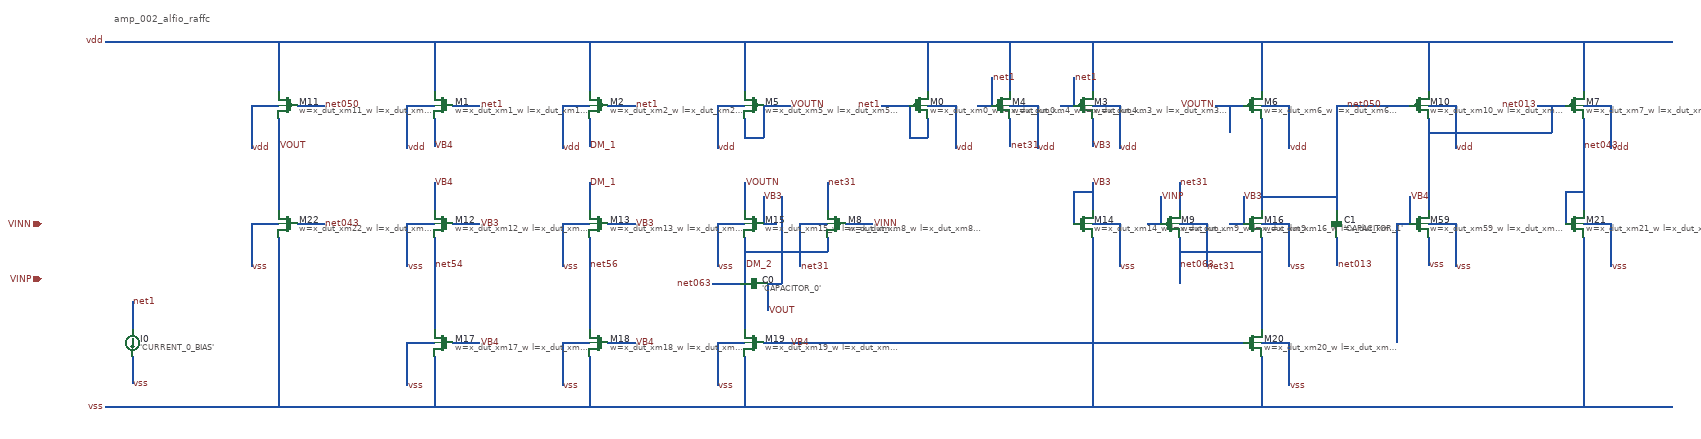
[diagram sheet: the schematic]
v {xschem version=3.4.6 file_version=1.2}
G {}
K {}
V {}
S {}
E {}
T {amp_002_alfio_raffc} -1740 -200 0 0 0.4 0.4 {}
C {devices/capa_np.sym} -340 390 1 0 {name=C0 value='CAPACITOR_0'}
C {devices/capa_np.sym} 935 260 0 0 {name=C1 value='CAPACITOR_1'}
C {devices/isource_np.sym} -1700 520 0 0 {name=I0 value='CURRENT_0_BIAS'}
C {devices/sg13_lv_pmos_np.sym} 20 0 0 0 {name=M0 model=sg13_lv_pmos spiceprefix=X w=x_dut_xm0_w l=x_dut_xm0_l m=x_dut_xm0_m}
C {devices/sg13_lv_pmos_np.sym} -1020 0 0 1 {name=M1 model=sg13_lv_pmos spiceprefix=X w=x_dut_xm1_w l=x_dut_xm1_l m=x_dut_xm1_m}
C {devices/sg13_lv_pmos_np.sym} 1115 0 0 0 {name=M10 model=sg13_lv_pmos spiceprefix=X w=x_dut_xm10_w l=x_dut_xm10_l m=x_dut_xm10_m}
C {devices/sg13_lv_pmos_np.sym} -1360 0 0 1 {name=M11 model=sg13_lv_pmos spiceprefix=X w=x_dut_xm11_w l=x_dut_xm11_l m=x_dut_xm11_m}
C {devices/sg13_lv_nmos_np.sym} -1020 260 0 1 {name=M12 model=sg13_lv_nmos spiceprefix=X w=x_dut_xm12_w l=x_dut_xm12_l m=x_dut_xm12_m}
C {devices/sg13_lv_nmos_np.sym} -680 260 0 1 {name=M13 model=sg13_lv_nmos spiceprefix=X w=x_dut_xm13_w l=x_dut_xm13_l m=x_dut_xm13_m}
C {devices/sg13_lv_nmos_np.sym} 380 260 0 0 {name=M14 model=sg13_lv_nmos spiceprefix=X w=x_dut_xm14_w l=x_dut_xm14_l m=x_dut_xm14_m}
C {devices/sg13_lv_nmos_np.sym} -340 260 0 1 {name=M15 model=sg13_lv_nmos spiceprefix=X w=x_dut_xm15_w l=x_dut_xm15_l m=x_dut_xm15_m}
C {devices/sg13_lv_nmos_np.sym} 750 260 0 0 {name=M16 model=sg13_lv_nmos spiceprefix=X w=x_dut_xm16_w l=x_dut_xm16_l m=x_dut_xm16_m}
C {devices/sg13_lv_nmos_np.sym} -1020 520 0 1 {name=M17 model=sg13_lv_nmos spiceprefix=X w=x_dut_xm17_w l=x_dut_xm17_l m=x_dut_xm17_m}
C {devices/sg13_lv_nmos_np.sym} -680 520 0 1 {name=M18 model=sg13_lv_nmos spiceprefix=X w=x_dut_xm18_w l=x_dut_xm18_l m=x_dut_xm18_m}
C {devices/sg13_lv_nmos_np.sym} -340 520 0 1 {name=M19 model=sg13_lv_nmos spiceprefix=X w=x_dut_xm19_w l=x_dut_xm19_l m=x_dut_xm19_m}
C {devices/sg13_lv_pmos_np.sym} -680 0 0 1 {name=M2 model=sg13_lv_pmos spiceprefix=X w=x_dut_xm2_w l=x_dut_xm2_l m=x_dut_xm2_m}
C {devices/sg13_lv_nmos_np.sym} 750 520 0 0 {name=M20 model=sg13_lv_nmos spiceprefix=X w=x_dut_xm20_w l=x_dut_xm20_l m=x_dut_xm20_m}
C {devices/sg13_lv_nmos_np.sym} 1455 260 0 0 {name=M21 model=sg13_lv_nmos spiceprefix=X w=x_dut_xm21_w l=x_dut_xm21_l m=x_dut_xm21_m}
C {devices/sg13_lv_nmos_np.sym} -1360 260 0 1 {name=M22 model=sg13_lv_nmos spiceprefix=X w=x_dut_xm22_w l=x_dut_xm22_l m=x_dut_xm22_m}
C {devices/sg13_lv_pmos_np.sym} 380 0 0 0 {name=M3 model=sg13_lv_pmos spiceprefix=X w=x_dut_xm3_w l=x_dut_xm3_l m=x_dut_xm3_m}
C {devices/sg13_lv_pmos_np.sym} 200 0 0 0 {name=M4 model=sg13_lv_pmos spiceprefix=X w=x_dut_xm4_w l=x_dut_xm4_l m=x_dut_xm4_m}
C {devices/sg13_lv_pmos_np.sym} -340 0 0 1 {name=M5 model=sg13_lv_pmos spiceprefix=X w=x_dut_xm5_w l=x_dut_xm5_l m=x_dut_xm5_m}
C {devices/sg13_lv_nmos_np.sym} 1115 260 0 0 {name=M59 model=sg13_lv_nmos spiceprefix=X w=x_dut_xm59_w l=x_dut_xm59_l m=x_dut_xm59_m}
C {devices/sg13_lv_pmos_np.sym} 750 0 0 0 {name=M6 model=sg13_lv_pmos spiceprefix=X w=x_dut_xm6_w l=x_dut_xm6_l m=x_dut_xm6_m}
C {devices/sg13_lv_pmos_np.sym} 1455 0 0 0 {name=M7 model=sg13_lv_pmos spiceprefix=X w=x_dut_xm7_w l=x_dut_xm7_l m=x_dut_xm7_m}
C {devices/sg13_lv_pmos_np.sym} -160 260 0 1 {name=M8 model=sg13_lv_pmos spiceprefix=X w=x_dut_xm8_w l=x_dut_xm8_l m=x_dut_xm8_m}
C {devices/sg13_lv_pmos_np.sym} 570 260 0 0 {name=M9 model=sg13_lv_pmos spiceprefix=X w=x_dut_xm9_w l=x_dut_xm9_l m=x_dut_xm9_m}
N -1700 430 -1700 490 {}
N -1700 550 -1700 610 {}
N -1440 0 -1440 94 {}
N -1440 260 -1440 354 {}
N -1380 -140 -1380 -30 {}
N -1380 30 -1380 230 {}
N -1380 290 -1380 660 {}
N -1100 0 -1100 94 {}
N -1100 260 -1100 354 {}
N -1100 520 -1100 614 {}
N -1040 -140 -1040 -30 {}
N -1040 30 -1040 90 {}
N -1040 170 -1040 230 {}
N -1040 290 -1040 490 {}
N -1040 550 -1040 660 {}
N -760 0 -760 94 {}
N -760 260 -760 354 {}
N -760 520 -760 614 {}
N -700 -140 -700 -30 {}
N -700 30 -700 90 {}
N -700 170 -700 230 {}
N -700 290 -700 490 {}
N -700 550 -700 660 {}
N -420 0 -420 94 {}
N -420 260 -420 354 {}
N -420 520 -420 614 {}
N -360 -140 -360 -30 {}
N -360 30 -360 70 {}
N -360 170 -360 230 {}
N -360 290 -360 490 {}
N -360 550 -360 660 {}
N -320 0 -320 70 {}
N -320 200 -320 260 {}
N -310 390 -310 450 {}
N -280 200 -280 390 {}
N -240 260 -240 354 {}
N -180 170 -180 230 {}
N -180 290 -180 320 {}
N 0 0 0 70 {}
N 40 -140 40 -30 {}
N 40 30 40 70 {}
N 100 0 100 94 {}
N 180 -60 180 0 {}
N 220 -140 220 -30 {}
N 220 30 220 90 {}
N 280 0 280 94 {}
N 360 -60 360 0 {}
N 360 190 360 260 {}
N 400 -140 400 -30 {}
N 400 30 400 90 {}
N 400 170 400 230 {}
N 400 290 400 660 {}
N 460 0 460 94 {}
N 460 260 460 354 {}
N 550 200 550 260 {}
N 590 170 590 230 {}
N 590 290 590 390 {}
N 650 260 650 354 {}
N 700 0 700 60 {}
N 730 200 730 260 {}
N 770 -140 770 -30 {}
N 770 30 770 230 {}
N 770 290 770 490 {}
N 770 550 770 660 {}
N 830 0 830 94 {}
N 830 260 830 354 {}
N 830 520 830 614 {}
N 935 0 935 230 {}
N 935 290 935 350 {}
N 1065 260 1065 520 {}
N 1095 200 1095 260 {}
N 1135 -140 1135 -30 {}
N 1135 30 1135 230 {}
N 1135 290 1135 350 {}
N 1195 0 1195 94 {}
N 1195 260 1195 354 {}
N 1405 0 1405 60 {}
N 1435 190 1435 260 {}
N 1475 -140 1475 -30 {}
N 1475 30 1475 230 {}
N 1475 290 1475 660 {}
N 1535 0 1535 94 {}
N 1535 260 1535 354 {}
N -1760 -140 1670 -140 {}
N -1440 0 -1380 0 {}
N -1340 0 -1280 0 {}
N -1100 0 -1040 0 {}
N -1000 0 -940 0 {}
N -760 0 -700 0 {}
N -660 0 -600 0 {}
N -420 0 -360 0 {}
N -320 0 -260 0 {}
N -60 0 0 0 {}
N 40 0 100 0 {}
N 150 0 180 0 {}
N 220 0 280 0 {}
N 330 0 360 0 {}
N 400 0 460 0 {}
N 670 0 730 0 {}
N 770 0 830 0 {}
N 935 0 1095 0 {}
N 1135 0 1195 0 {}
N 1375 0 1435 0 {}
N 1475 0 1535 0 {}
N 1135 60 1405 60 {}
N -360 70 -320 70 {}
N 0 70 40 70 {}
N 360 190 400 190 {}
N 1435 190 1475 190 {}
N 770 200 935 200 {}
N -1440 260 -1380 260 {}
N -1340 260 -1280 260 {}
N -1100 260 -1040 260 {}
N -1000 260 -940 260 {}
N -760 260 -700 260 {}
N -660 260 -600 260 {}
N -420 260 -360 260 {}
N -320 260 -290 260 {}
N -240 260 -180 260 {}
N -140 260 -80 260 {}
N 400 260 460 260 {}
N 520 260 550 260 {}
N 590 260 650 260 {}
N 700 260 730 260 {}
N 770 260 830 260 {}
N 1065 260 1095 260 {}
N 1135 260 1195 260 {}
N 1475 260 1535 260 {}
N -360 320 -180 320 {}
N 590 320 770 320 {}
N -430 390 -370 390 {}
N -310 390 -280 390 {}
N -1100 520 -1040 520 {}
N -1000 520 -940 520 {}
N -760 520 -700 520 {}
N -660 520 -600 520 {}
N -420 520 -360 520 {}
N -320 520 730 520 {}
N 770 520 830 520 {}
N -1760 660 1670 660 {}
C {devices/lab_wire.sym} -1760 -140 0 0 {name=l0 lab=vdd}
C {devices/lab_wire.sym} -1760 660 0 0 {name=l1 lab=vss}
C {devices/lab_wire.sym} -700 90 2 0 {name=l2 lab=DM_1}
C {devices/lab_wire.sym} -700 170 0 1 {name=l3 lab=DM_1}
C {devices/lab_wire.sym} -360 350 2 0 {name=l4 lab=DM_2}
C {devices/lab_wire.sym} -940 260 0 1 {name=l5 lab=VB3}
C {devices/lab_wire.sym} -600 260 0 1 {name=l6 lab=VB3}
C {devices/lab_wire.sym} -320 200 0 1 {name=l7 lab=VB3}
C {devices/lab_wire.sym} 400 170 0 1 {name=l8 lab=VB3}
C {devices/lab_wire.sym} 400 90 2 0 {name=l9 lab=VB3}
C {devices/lab_wire.sym} 730 200 0 1 {name=l10 lab=VB3}
C {devices/lab_wire.sym} -1040 90 2 0 {name=l11 lab=VB4}
C {devices/lab_wire.sym} -1040 170 0 1 {name=l12 lab=VB4}
C {devices/lab_wire.sym} -940 520 0 1 {name=l13 lab=VB4}
C {devices/lab_wire.sym} -600 520 0 1 {name=l14 lab=VB4}
C {devices/lab_wire.sym} -260 520 0 1 {name=l15 lab=VB4}
C {devices/lab_wire.sym} 1095 200 0 1 {name=l16 lab=VB4}
C {devices/lab_wire.sym} -80 260 0 1 {name=l17 lab=VINN}
C {devices/lab_wire.sym} 550 200 0 1 {name=l18 lab=VINP}
C {devices/lab_wire.sym} -1380 90 2 0 {name=l19 lab=VOUT}
C {devices/lab_wire.sym} -310 450 2 0 {name=l20 lab=VOUT}
C {devices/lab_wire.sym} -260 0 0 1 {name=l21 lab=VOUTN}
C {devices/lab_wire.sym} -360 170 0 1 {name=l22 lab=VOUTN}
C {devices/lab_wire.sym} 670 0 0 0 {name=l23 lab=VOUTN}
C {devices/lab_wire.sym} 935 350 2 0 {name=l24 lab=net013}
C {devices/lab_wire.sym} 1375 0 0 0 {name=l25 lab=net013}
C {devices/lab_wire.sym} -1280 260 0 1 {name=l26 lab=net043}
C {devices/lab_wire.sym} 1475 90 2 0 {name=l27 lab=net043}
C {devices/lab_wire.sym} -1280 0 0 1 {name=l28 lab=net050}
C {devices/lab_wire.sym} 1035 0 0 0 {name=l29 lab=net050}
C {devices/lab_wire.sym} -430 390 0 0 {name=l30 lab=net063}
C {devices/lab_wire.sym} 590 350 2 0 {name=l31 lab=net063}
C {devices/lab_wire.sym} -940 0 0 1 {name=l32 lab=net1}
C {devices/lab_wire.sym} -600 0 0 1 {name=l33 lab=net1}
C {devices/lab_wire.sym} -60 0 0 0 {name=l34 lab=net1}
C {devices/lab_wire.sym} 180 -60 0 1 {name=l35 lab=net1}
C {devices/lab_wire.sym} 360 -60 0 1 {name=l36 lab=net1}
C {devices/lab_wire.sym} -180 170 0 1 {name=l37 lab=net31}
C {devices/lab_wire.sym} 220 90 2 0 {name=l38 lab=net31}
C {devices/lab_wire.sym} 590 170 0 1 {name=l39 lab=net31}
C {devices/lab_wire.sym} -1040 350 2 0 {name=l40 lab=net54}
C {devices/lab_wire.sym} -700 350 2 0 {name=l41 lab=net56}
C {devices/lab_wire.sym} -240 354 2 0 {name=l42 lab=net31}
C {devices/lab_wire.sym} 650 354 2 0 {name=l43 lab=net31}
C {devices/lab_wire.sym} 100 94 2 0 {name=l44 lab=vdd}
C {devices/lab_wire.sym} -1100 94 2 0 {name=l45 lab=vdd}
C {devices/lab_wire.sym} 1195 94 2 0 {name=l46 lab=vdd}
C {devices/lab_wire.sym} -1440 94 2 0 {name=l47 lab=vdd}
C {devices/lab_wire.sym} -760 94 2 0 {name=l48 lab=vdd}
C {devices/lab_wire.sym} 460 94 2 0 {name=l49 lab=vdd}
C {devices/lab_wire.sym} 280 94 2 0 {name=l50 lab=vdd}
C {devices/lab_wire.sym} -420 94 2 0 {name=l51 lab=vdd}
C {devices/lab_wire.sym} 830 94 2 0 {name=l52 lab=vdd}
C {devices/lab_wire.sym} 1535 94 2 0 {name=l53 lab=vdd}
C {devices/lab_wire.sym} -1100 354 2 0 {name=l54 lab=vss}
C {devices/lab_wire.sym} -760 354 2 0 {name=l55 lab=vss}
C {devices/lab_wire.sym} 460 354 2 0 {name=l56 lab=vss}
C {devices/lab_wire.sym} -420 354 2 0 {name=l57 lab=vss}
C {devices/lab_wire.sym} 830 354 2 0 {name=l58 lab=vss}
C {devices/lab_wire.sym} -1100 614 2 0 {name=l59 lab=vss}
C {devices/lab_wire.sym} -760 614 2 0 {name=l60 lab=vss}
C {devices/lab_wire.sym} -420 614 2 0 {name=l61 lab=vss}
C {devices/lab_wire.sym} 830 614 2 0 {name=l62 lab=vss}
C {devices/lab_wire.sym} 1535 354 2 0 {name=l63 lab=vss}
C {devices/lab_wire.sym} -1440 354 2 0 {name=l64 lab=vss}
C {devices/lab_wire.sym} 1195 354 2 0 {name=l65 lab=vss}
C {devices/lab_wire.sym} -1700 430 0 1 {name=l66 lab=net1}
C {devices/lab_wire.sym} -1700 610 2 0 {name=l67 lab=vss}
C {devices/lab_wire.sym} 1135 350 2 0 {name=l68 lab=vss}
C {devices/ipin.sym} -1900 260 0 0 {name=p0 lab=VINN}
C {devices/ipin.sym} -1900 380 0 0 {name=p1 lab=VINP}
